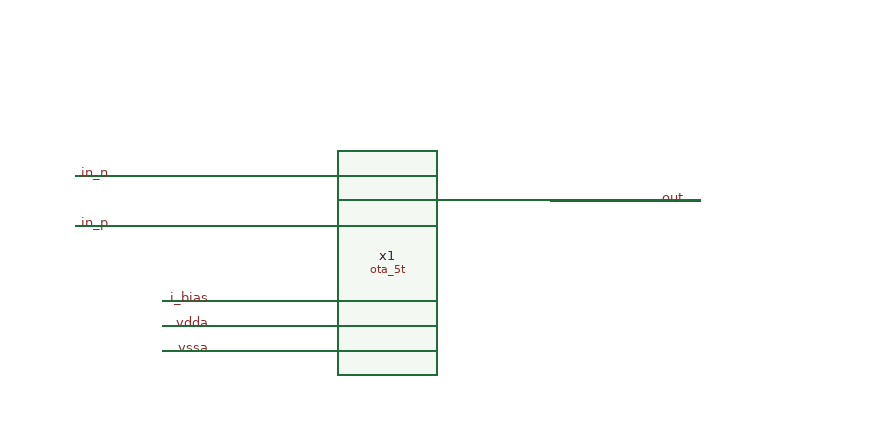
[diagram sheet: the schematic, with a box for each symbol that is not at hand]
v {xschem version=3.4.7 file_version=1.2}
G {}
K {}
V {}
S {}
E {}
N 410 -240 460 -240 {lab=out}
N 460 -240 530 -240 {lab=out}
N 100 -140 160 -140 {lab=vdda}
N 100 -120 160 -120 {lab=vssa}
N 30 -220 160 -220 {lab=in_p}
N 100 -160 160 -160 {lab=i_bias}
N 30 -260 160 -260 {lab=in_n}
C {devices/lab_wire.sym} 520 -240 0 0 {name=p1 sig_type=std_logic lab=out}
C {devices/lab_wire.sym} 140 -140 0 0 {name=p4 sig_type=std_logic lab=vdda}
C {devices/lab_wire.sym} 140 -120 0 0 {name=p5 sig_type=std_logic lab=vssa}
C {devices/lab_wire.sym} 60 -220 0 0 {name=p9 sig_type=std_logic lab=in_p}
C {libs/core_analog/ota_5t/ota_5t.sym} 180 -330 0 0 {name=x1}
C {devices/lab_wire.sym} 140 -160 0 0 {name=p2 sig_type=std_logic lab=i_bias}
C {devices/lab_wire.sym} 60 -260 0 0 {name=p3 sig_type=std_logic lab=in_n}
